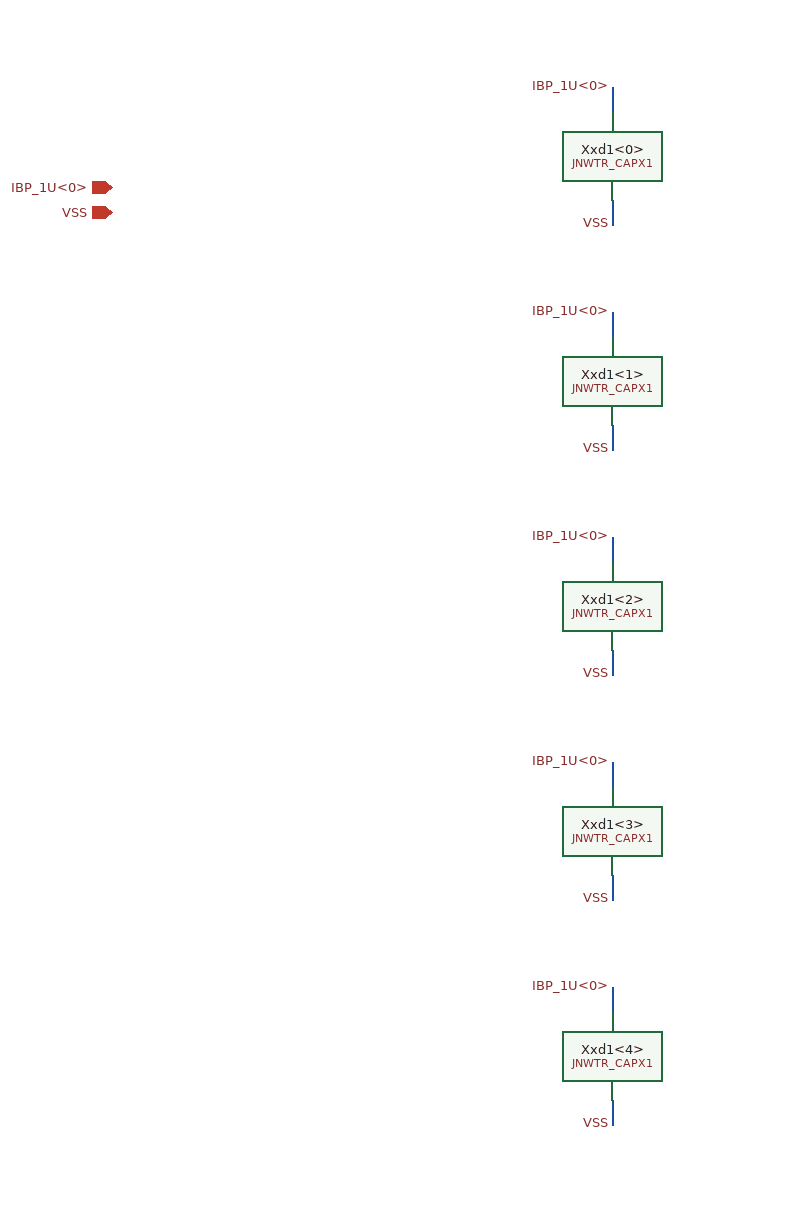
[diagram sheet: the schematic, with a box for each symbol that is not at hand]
v {xschem version=3.0.0 file_version=1.2 }
G {}
K {}
V {}
S {}
E {}
C {devices/iopin.sym} 0 0 0 0 {name=p0 lab=IBP_1U<0>}
C {devices/iopin.sym} 0 20 0 0 {name=p1 lab=VSS}
C {JNW_TR_SKY130A/JNWTR_CAPX1.sym} 400 0 0 0 {name=Xxd1<0>}
N 400.0 -80.0 400.0 -60.0 {lab=IBP_1U<0>}
C {devices/lab_pin.sym} 400.0 -80.0 3 0 {name=l0 sig_type=std_logic lab=IBP_1U<0> }
N 400.0 30.0 400.0 10.0 {lab=VSS}
C {devices/lab_pin.sym} 400.0 30.0 1 0 {name=l1 sig_type=std_logic lab=VSS }
C {JNW_TR_SKY130A/JNWTR_CAPX1.sym} 400 180.0 0 0 {name=Xxd1<1>}
N 400.0 100.0 400.0 120.0 {lab=IBP_1U<0>}
C {devices/lab_pin.sym} 400.0 100.0 3 0 {name=l2 sig_type=std_logic lab=IBP_1U<0> }
N 400.0 210.0 400.0 190.0 {lab=VSS}
C {devices/lab_pin.sym} 400.0 210.0 1 0 {name=l3 sig_type=std_logic lab=VSS }
C {JNW_TR_SKY130A/JNWTR_CAPX1.sym} 400 360.0 0 0 {name=Xxd1<2>}
N 400.0 280.0 400.0 300.0 {lab=IBP_1U<0>}
C {devices/lab_pin.sym} 400.0 280.0 3 0 {name=l4 sig_type=std_logic lab=IBP_1U<0> }
N 400.0 390.0 400.0 370.0 {lab=VSS}
C {devices/lab_pin.sym} 400.0 390.0 1 0 {name=l5 sig_type=std_logic lab=VSS }
C {JNW_TR_SKY130A/JNWTR_CAPX1.sym} 400 540.0 0 0 {name=Xxd1<3>}
N 400.0 460.0 400.0 480.0 {lab=IBP_1U<0>}
C {devices/lab_pin.sym} 400.0 460.0 3 0 {name=l6 sig_type=std_logic lab=IBP_1U<0> }
N 400.0 570.0 400.0 550.0 {lab=VSS}
C {devices/lab_pin.sym} 400.0 570.0 1 0 {name=l7 sig_type=std_logic lab=VSS }
C {JNW_TR_SKY130A/JNWTR_CAPX1.sym} 400 720.0 0 0 {name=Xxd1<4>}
N 400.0 640.0 400.0 660.0 {lab=IBP_1U<0>}
C {devices/lab_pin.sym} 400.0 640.0 3 0 {name=l8 sig_type=std_logic lab=IBP_1U<0> }
N 400.0 750.0 400.0 730.0 {lab=VSS}
C {devices/lab_pin.sym} 400.0 750.0 1 0 {name=l9 sig_type=std_logic lab=VSS }
